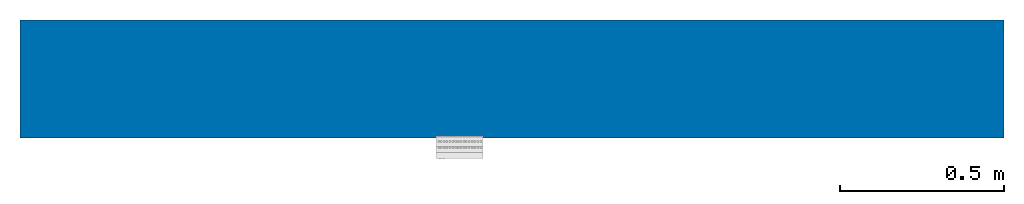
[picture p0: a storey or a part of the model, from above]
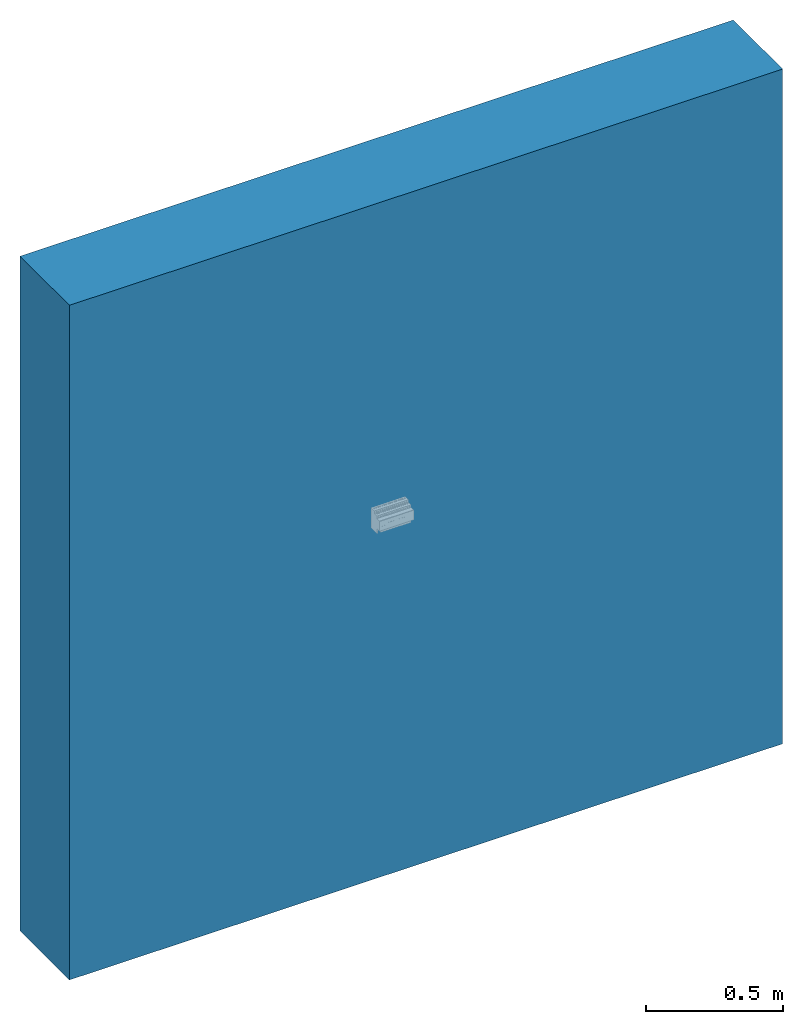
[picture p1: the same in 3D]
Properties of the parts of a building model (IFC2X3)

# File
Description: ViewDefinition [CoordinationView_V2.0]
File name: Projektnummer
Time: 2019-08-29T13:27:01
Written by: The EXPRESS Data Manager Version 5.02.0100.07 : 28 Aug 2013
Made in: 20160225_1515(x64) - Exporter 17.0.416.0 - Alternate UI 17.12.14.0
Comment: STEP Physical File produced by: The EXPRESS Data Manager Version 5.02.0100.07 : 28 Aug 2013 * Module: EDMstepFileFactory/EDMstandAlone * Creation date: Thu Aug 29 13:27:01 2019 * Host: B-BIM-NB-4736 * Database: C:\Users\Enkler\AppData\Local\Temp\{895A7849-E6DB-4E4F-883F-3BA8C0A199C4}\ifc * Database version: 5507 * Database creation date: Thu Aug 29 13:26:59 2019 * Schema: IFC2X3 * Model: DataRepository.ifc * Model creation date: Thu Aug 29 13:26:59 2019 * Header model: DataRepository.ifc_HeaderModel * Header model creation date: Thu Aug 29 13:26:59 2019 * EDMuser: sdai-user * EDMgroup: sdai-group * License ID and type: 5605 : Permanent license. Expiry date: * EDMstepFileFactory options: 020000

# IfcProject, Projektnummer
LongName: Projektname; Phase: Projektstatus

# IfcSite, Default
RefLatitude: 52, 30, 59, 765625; RefLongitude: 13, 23, 59, 998626; RefElevation: 0 m
Sonstige - Kategorie: Projektinformationen; Kundenname: Bauherr; Projektadresse: Projektadresse; Projektausgabedatum: Projekt Datum; Projektname: Projektname; Projektnummer: Projektnummer; Projektstatus: Projektstatus; Verfasser eMail: E-Mail; Verfasser Firma 1: Firma 1; Verfasser Firma 2: Firma 2; Verfasser PLZ Ort: PLZ Ort; Verfasser Strasse: Strasse; Verfasser Telefax: Telefax; Verfasser Telefon: Telefon

# IfcBuilding
Pset_BuildingCommon - NumberOfStoreys: 1
Sonstige - Kategorie: Projektinformationen; Kundenname: Bauherr; Projektadresse: Projektadresse; Projektausgabedatum: Projekt Datum; Projektname: Projektname; Projektnummer: Projektnummer; Projektstatus: Projektstatus; Verfasser eMail: E-Mail; Verfasser Firma 1: Firma 1; Verfasser Firma 2: Firma 2; Verfasser PLZ Ort: PLZ Ort; Verfasser Strasse: Strasse; Verfasser Telefax: Telefax; Verfasser Telefon: Telefon

# IfcBuildingStorey, Ebene 0
LongName: Ebene 0; Elevation: 0 m
Sonstige - Kategorie: Ebenen; Familienname: Ebene; Familie: Ebene: Ebene; Familie und Typ: Ebene: Ebene; Typ: Ebene: Ebene; Typ-ID: Ebene: Ebene
ID-Daten - Typname: Ebene; Tragwerk: no; Gebäudegeschoss: yes; Name: Ebene 0
Grafiken - Farbe: 16711680; Linienmuster: Verdeckt; Linienstärke: 1; Symbol: Beschriftung Ebene: Beschriftung Ebene; Symbol bei Ende 1 Standard: no; Symbol bei Ende 2 Standard: yes
Abhängigkeiten - Basishöhe: Projekt-Basispunkt; Ansicht: 0 m
Abmessungen - Höhe für Berechnung: 0 m

# IfcBuildingElementProxy: GIRA_217400_ENG, GIRA_217400_ENG:GIRA_217400_ENG:389842
In: Ebene 0
Type - Material: White
Type - Abhängigkeiten - Vorgabe-Ansicht: 1.2192 m
Type - Allgemein - Bus connection included: yes; Bus connection included YesNo: yes; Bus system KNX: yes; Bus system KNX radio: no; Bus system KNX radio YesNo: no; Bus system KNX YesNo: yes; Bus system LON: no; Bus system LON YesNo: no; Bus system Powernet: no; Bus system Powernet YesNo: no; Bus system radio frequent: no; Bus system radio frequent YesNo: no; Degree of protection (IP): IP20; Degree of protection (IP) Text: IP21; HeinzeBIM: https://www.heinze.de/bim/dimm-act-4-g-4-x-250-w-va-knx-dra/f94cfc6071d9e28133d19dab837e799b8359b49c; Local operation/hand operation: yes; Local operation/hand operation YesNo: yes; Model: Dimming actuator; Mounting method: DRA (DIN-rail adapter); Mounting method Text: DRA (DIN-rail adapter); Substation input YesNo: no; With LED indication: no; With LED indication YesNo: no
Type - Daten - Max. number of venetian-blind outputs: 8; Number of outputs Number: 4; Width in number of modular spacings: 8; Width in number of modular spacings Number: 8
Type - ID-Daten - Beschreibung: Dimm.act.4g 4x250W VA DRA KNX,KNX dimming actuator, 4-gang,4 x 250 W VA,DRA plus,Features:,- Dim actuator with integrated bus coupler.,- Switching and dimming of light bulbs, HV halogen lamps, dimmable HV-LED lamps, dimmable compact fluorescent lamps, dimmable inductive transformers with LV halogen or NV-LED lamps, dimmable electronic transformers with LV halogen or NV-LED lamps.,- Automatic or manual selection of dimming principle according to load.,- Idle-state, short-circuit, and excess temperature-proof,- Manual actuation of the outputs independent of the bus (building site operation also possible).,- Several outputs can be wired in parallel to increase output power.,- Parallel switching of several outputs to a load of 950 W possible. Do not connect LED or compact fluorescent lamps to dimming outputs connected in parallel.,- Building site operation: Outputs can be operated manually without bus voltage with operating voltage only.,Functions:,- Central switching function for control of all dimming channels.,- Delay for actively transmitted feedback messages following bus voltage recovery.,- Load type and dimming method can be configured: Universal (with automatic calibration procedure), electronic transformer LV LED (capacitive phase cut), conventional transformer LV LED (inductive phase cut), HV LED (phase cut) or HV LED (phase cut).,- Feedback for switching" and "brightness value".,- Dimmable brightness range can be set.,- Dimming behaviour and dimming characteristics can be parameterised.,- Switch-on behaviour for a relative dimming command can be parameterised.,- Bulb-saving switch-on and switch-off,- Automatic setting and scaling of the dimmable brightness range when using universal power boosters.,- The performance of a dimming channel in the "OFF" state during reception of a relative dimming command can be parameterised (switching and dimming or no response).,- Alarm telegrams for short circuit, overload, and load failure.,- Feedback of connected load type.,- Block function or forced setting function can be parameterised for each output.,- Time functions (switch-on off delay, staircase light function).,- Staircase light function with advance warning function via time-controlled reduction of lighting or activation of permanent lighting.,- Linking function and up to eight scenes per dimming channel possible.,- Elapsed operating time meter for recording switch-on time.,- Reactions after bus voltage failure and recovery can be set.,,Notes :,- Power extension using Gira power boosters.,- Installation on DIN top-hat rail.,- VDE approval in accordance with EN 60669-1, EN 60669-2-1."; GTIN: 4010337082224; HAN: 217400; Hersteller: Gira; Typname: GIRA_217400_ENG; URL: https://www.gira.de/
Type - Sonstige - Kategorie: Elektroinstallationen; Familienname: GIRA_217400_ENG
Pset_BuildingElementProxyCommon - Reference: GIRA_217400_ENG
Pset_ManufacturerTypeInformation - Manufacturer: Gira
Abhängigkeiten - Basisbauteil: Basiswand : MW 24.0 WD 12.0; Ebene: Ebene: Ebene 0; Erhebung: 1.61133 m
Abmessungen - Fläche: 0.029516 m2; Volumen: 0.000917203 m3
ID-Daten - Kennzeichen: 1
Phasen - Phase erstellt: Phase 1
Sonstige - Bauteillistenebene: Ebene: Ebene 0; Familie: GIRA_217400_ENG: GIRA_217400_ENG; Familie und Typ: GIRA_217400_ENG: GIRA_217400_ENG; Typ: GIRA_217400_ENG: GIRA_217400_ENG; Typ-ID: GIRA_217400_ENG: GIRA_217400_ENG

# IfcWallStandardCase: Basiswand:MW 24.0 WD 12.0, Basiswand:MW 24.0 WD 12.0:388640
In: Ebene 0
Type - PredefinedType: STANDARD; Material: Wärmedämmung - hart 0.12 m, Mauerwerk - Ziegel, verputzt 0.24 m
Type - Analytische Eigenschaften - Absorptionsgrad: 0.7; Rauigkeit: 3; Thermischer Widerstand (R): 3.87302; Thermisch wirksame Masse: 316537; Wärmeübergangskoeffizient (U): 0.258197
Type - Grafiken - Farbfüllung für groben Maßstab: 0; Füllmuster für groben Maßstab: Standard - Füllung
Type - ID-Daten - Beschreibung: Mauerwerk 24.0 cm, Wärmedämmung 12.0 cm; Typenkommentare: Mehrschaliges Mauerwerk; Typname: MW 24.0 WD 12.0
Type - Konstruktion - Abschluss an Öffnungen: Keine; Abschluss an Wänden: Keine; Breite: 0.36 m; Funktion: Außen
Type - Materialien und Oberflächen - Tragendes Material: Mauerwerk - Ziegel, verputzt
Type - Sonstige - Kategorie: Wände; Familienname: Basiswand
Abhängigkeiten - Abhängigkeit oben: Ebene: Ebene 1; Abhängigkeit unten: Ebene: Ebene 0; Basislinie: Wandachse; Für Körper: no; Nicht verknüpfte Höhe: 3 m; Oberkante ist fixiert.: no; Raumbegrenzung: yes; Unterkante ist fixiert: no; Verlängerungsabstand oben: 0 m; Verlängerungsabstand unten: 0 m; Versatz oben: 0 m; Versatz unten: 0 m
Abmessungen - Fläche: 9 m2; Länge: 3 m; Volumen: 3.24 m3
Phasen - Phase erstellt: Phase 1
Sonstige - Familie: Basiswand: MW 24.0 WD 12.0; Familie und Typ: Basiswand: MW 24.0 WD 12.0; Typ: Basiswand: MW 24.0 WD 12.0; Typ-ID: Basiswand: MW 24.0 WD 12.0
Tragwerk - Berechnungsmodell aktivieren: no; Tragwerk: no; Tragwerksverwendung: Nichttragend
Pset_WallCommon - Reference: MW 24.0 WD 12.0; LoadBearing: no; ExtendToStructure: no; IsExternal: yes; ThermalTransmittance: 0.258197 kg/K/s3
